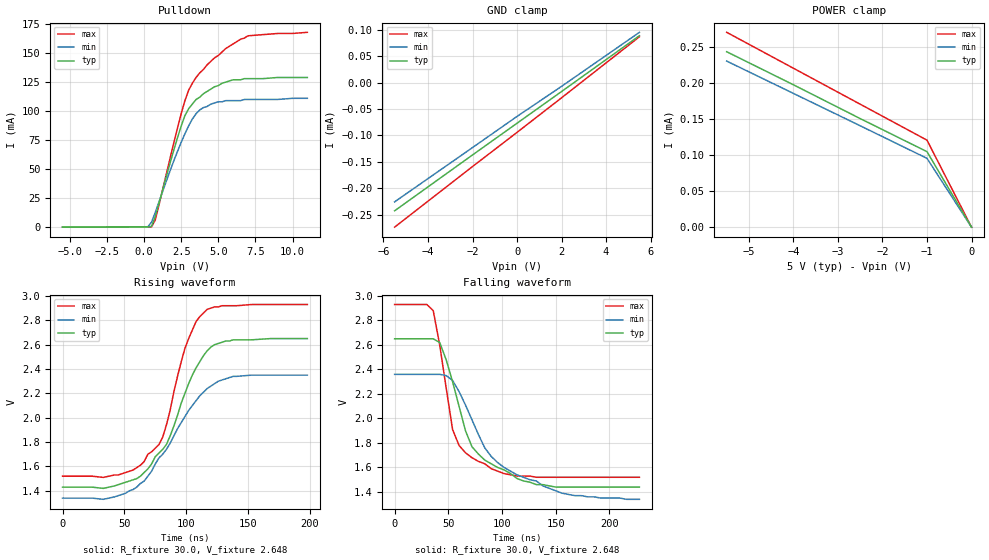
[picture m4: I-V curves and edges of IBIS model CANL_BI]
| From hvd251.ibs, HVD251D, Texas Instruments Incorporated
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|   Driver (CANL) Output/Receiver Input Model
[Model]   CANL_BI
Model_type   I/O_open_drain
| Signals   CANH
Vinh = 0.9V
Vinl = 0.5V
Rref = 30   |Note: 60 Ohm differential load;
Vref = 2.3   |tr, tf measured in single ended configuration
| variable   typ   min   max
C_comp   1.0pF   NA   NA
|   typ   min   max
[Temperature Range]   25.0   -40   125
[Voltage Range]   5.0V   4.5V   5.5V
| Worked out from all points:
|   slope of the pulldown table from 0 to 0.75 V, typ, clamps not added: 84.4 ohm
|   rising waveform, R_fixture 30.0, V_fixture 2.648: 20-80 % time 33.1ns typ, 38ns min, 22.8ns max; typ from 1.43 V to 2.65 V
|   falling waveform, R_fixture 30.0, V_fixture 2.648: 20-80 % time 31ns typ, 49.7ns min, 18ns max; typ from 2.65 V to 1.44 V
[Pulldown]
|   Voltage   I(typ)   I(min)   I(max)
-5.5V     -243uA     -226uA     -274uA
250mV     -72.3uA    20.6uA     -87.7uA
500mV     382uA      4.06mA     -72.2uA
750mV     8.81mA     12.4mA     5.92mA
2.5V      87.1mA     73.1mA     97.8mA
3V        102mA      87.2mA     118mA
3.5V      110mA      97.7mA     129mA
4V        115mA      103mA      136mA
5V        122mA      108mA      148mA
6V        127mA      109mA      158mA
7V        128mA      110mA      165mA
11V       129mA      111mA      168mA
[Power_clamp]
| Note that the[POWER_clamp]voltage table is referenced to Vcc
| and is calculated using Vtable=Vcc - Vmeasured.
|   Voltage   I(typ)   I(min)   I(max)
-5.5V     244uA      231uA      271uA
-4V       198uA      186uA      221uA
-2.5V     151uA      141uA      171uA
-1V       105uA      95.7uA     121uA
0V        0A         0A         0A
[GND_clamp]
|   Voltage   I(typ)   I(min)   I(max)
-5.5V     -243uA     -226uA     -274uA
-2V       -137uA     -123uA     -159uA
0V        -76.8uA    -63.9uA    -94.2uA
2V        -16.7uA    -6.87uA    -28.6uA
5.5V      89.3uA     95.7uA     87.3uA
[Ramp]
|   typ   min   max
dV/dt_r   1.21/48ns   1.01/57ns   1.41/42ns
dV/dt_f   1.21/63ns   1.01/84ns   1.41/36ns
R_load = 30ohm  | Note: The measurement is single-ended with 30ohm
|   to Vfixture
[Rising Waveform]
R_fixture = 30.0
V_fixture = 2.648
V_fixture_min = 2.356
V_fixture_max = 2.927
C_fixture = 0p
L_fixture = 0n
|   V(typ)   V(min)   V(max)
0s        1.43V      1.34V      1.52V
51ns      1.47V      1.38V      1.55V
66ns      1.55V      1.48V      1.64V
78ns      1.71V      1.67V      1.78V
84ns      1.78V      1.74V      1.94V
99ns      2.2V       2.01V      2.57V
108ns     2.41V      2.14V      2.79V
117ns     2.55V      2.24V      2.89V
138ns     2.64V      2.34V      2.92V
198ns     2.65V      2.35V      2.93V
[Falling Waveform]
R_fixture = 30.0
V_fixture = 2.648
V_fixture_min = 2.356
V_fixture_max = 2.927
C_fixture = 0p
L_fixture = 0n
|   V(typ)   V(min)   V(max)
0s        2.65V      2.36V      2.93V
36ns      2.65V      2.36V      2.88V
42ns      2.62V      2.36V      2.6V
54ns      2.3V       2.31V      1.91V
60ns      2.1V       2.22V      1.78V
72ns      1.77V      1.99V      1.68V
90ns      1.63V      1.69V      1.59V
114ns     1.51V      1.54V      1.53V
156ns     1.44V      1.39V      1.52V
228ns     1.44V      1.34V      1.52V
